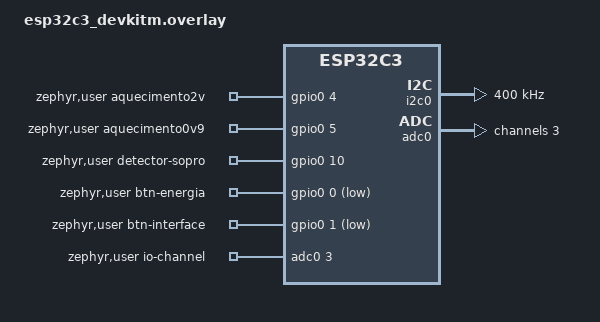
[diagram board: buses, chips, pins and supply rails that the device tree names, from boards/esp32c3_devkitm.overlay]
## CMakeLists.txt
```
cmake_minimum_required(VERSION 3.20.0)

find_package(Zephyr REQUIRED HINTS $ENV{ZEPHYR_BASE})
project(bafometro)

include(${CMAKE_CURRENT_SOURCE_DIR}/fontes.cmake)

target_include_directories(app PRIVATE ${BAFOMETRO_INCLUDES})
target_sources(app PRIVATE src/main.c ${BAFOMETRO_FONTES})
target_sources_ifdef(CONFIG_BAFOMETRO_ROTEIRO_SIMULACAO app PRIVATE src/simulacao/roteiro.c)
```

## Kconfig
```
menu "Bafômetro"

config BAFOMETRO_TEMPOS_REDUZIDOS
	bool "Tempos de espera reduzidos"
	help
	  Divide por 10 os tempos de pré-aquecimento, espera pelo sopro,
	  apresentação, recuperação e acomodação, para demonstrações em
	  hardware. A coleta de 5 s e os períodos de amostragem não mudam.

config BAFOMETRO_ROTEIRO_SIMULACAO
	bool "Roteiro de simulação"
	default y if BOARD_NATIVE_SIM
	depends on GPIO_EMUL
	help
	  Percorre o fluxo completo no native_sim, acionando o detector pelo
	  GPIO emulado e enviando comandos pela fila de eventos, e encerra a
	  simulação ao final.

endmenu

source "Kconfig.zephyr"
```

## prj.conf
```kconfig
# Máquina de estados e entradas digitais
CONFIG_SMF=y
CONFIG_GPIO=y

# Registro de eventos
CONFIG_LOG=y
CONFIG_LOG_DEFAULT_LEVEL=3

CONFIG_MAIN_STACK_SIZE=2048
```

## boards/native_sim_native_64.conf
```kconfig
# Simulação o mais rápido possível; para tempo real, execute com --rt.
CONFIG_NATIVE_SIM_SLOWDOWN_TO_REAL_TIME=n
```

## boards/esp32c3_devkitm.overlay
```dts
/*
 * ESP32-C3-DevKitM-1: pinagem de docs/hardware.md.
 * Na etapa 1 só o detector de sopro (GPIO10) é usado; para simular um sopro,
 * ligue o GPIO10 ao 3V3.
 */

#include <zephyr/dt-bindings/pinctrl/esp32c3-pinctrl.h>
#include <zephyr/dt-bindings/adc/adc.h>
#include <zephyr/dt-bindings/gpio/gpio.h>
#include <zephyr/dt-bindings/i2c/i2c.h>

&pinctrl {
	i2c0_bafometro: i2c0_bafometro {
		group1 {
			pinmux = <I2C0_SDA_GPIO6>, <I2C0_SCL_GPIO7>;
			bias-pull-up;
			drive-open-drain;
			output-high;
		};
	};
};

/* A placa habilita o SPI2 em GPIO2/6/7/10, que conflita com o I2C e o detector. */
&spi2 {
	status = "disabled";
};

&i2c0 {
	status = "okay";
	pinctrl-0 = <&i2c0_bafometro>; /* a placa usa GPIO1/GPIO3 por padrão; GPIO3 é o ADC */
	pinctrl-names = "default";
	clock-frequency = <I2C_BITRATE_FAST>; /* 400 kbit/s */
};

&adc0 {
	status = "okay";
	#address-cells = <1>;
	#size-cells = <0>;

	channel@3 {
		reg = <3>; /* ADC1_CH3 = GPIO3 */
		zephyr,gain = "ADC_GAIN_1_4"; /* atenuação 11 dB -> 0..2500 mV */
		zephyr,reference = "ADC_REF_INTERNAL"; /* única referência aceita */
		zephyr,acquisition-time = <ADC_ACQ_TIME_DEFAULT>; /* não parametrizável */
		zephyr,resolution = <12>; /* única resolução no C3 */
	};
};

/ {
	zephyr,user {
		io-channels = <&adc0 3>;
		/* Polaridade dos enables do aquecedor: confirmar no esquemático. */
		aquecimento2v-gpios = <&gpio0 4 GPIO_ACTIVE_HIGH>;
		aquecimento0v9-gpios = <&gpio0 5 GPIO_ACTIVE_HIGH>;
		detector-sopro-gpios = <&gpio0 10 (GPIO_ACTIVE_HIGH | GPIO_PULL_DOWN)>;
		btn-energia-gpios = <&gpio0 0 (GPIO_ACTIVE_LOW | GPIO_PULL_UP)>;
		btn-interface-gpios = <&gpio0 1 (GPIO_ACTIVE_LOW | GPIO_PULL_UP)>;
		/* inibidor-gpios: pino pendente (ver docs/hardware.md) */
	};
};
```

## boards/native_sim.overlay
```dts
/*
 * Detector de sopro no GPIO emulado do native_sim (pino 0).
 * O roteiro de simulação e os testes o acionam com gpio_emul_input_set().
 */

#include <zephyr/dt-bindings/gpio/gpio.h>

/ {
	zephyr,user {
		detector-sopro-gpios = <&gpio0 0 GPIO_ACTIVE_HIGH>;
	};
};
```

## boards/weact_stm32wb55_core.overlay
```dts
/*
 * Provisório (etapa 1): o botão BOOT da placa (PH3) faz o papel do detector
 * de sopro. A pinagem do bafômetro no STM32WB55 é definida na etapa 8.
 */

#include <zephyr/dt-bindings/gpio/gpio.h>

/ {
	zephyr,user {
		detector-sopro-gpios = <&gpioh 3 (GPIO_ACTIVE_HIGH | GPIO_PULL_DOWN)>;
	};
};
```

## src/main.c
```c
/*
 * Bafômetro: ponto de entrada. A única thread da aplicação processa a fila
 * de eventos e executa a máquina de estados.
 */

#include <zephyr/kernel.h>

#include "aplicacao/bafometro.h"

int main(void)
{
	(void)bafometro_iniciar();

	while (true) {
		(void)bafometro_processarProximoEvento(K_FOREVER);
	}

	return 0;
}
```

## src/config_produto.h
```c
/*
 * Parâmetros do produto: fonte única dos valores usados pela aplicação.
 * A origem de cada valor está em docs/arquitetura/arquitetura-firmware.md.
 * Só macros: este arquivo é incluído também pelo domínio, que não depende do Zephyr.
 */

#ifndef BAFOMETRO_CONFIG_PRODUTO_H
#define BAFOMETRO_CONFIG_PRODUTO_H

#if defined(CONFIG_BAFOMETRO_TEMPOS_REDUZIDOS)
#define FATOR_REDUCAO_TEMPO 10U
#else
#define FATOR_REDUCAO_TEMPO 1U
#endif

/*
 * Esperas do fluxo, divididas pelo fator de redução.
 * Pré-aquecimento: o datasheet do MQ303B (v1.4) pede 2,0 V por 5 a 10 s antes da detecção.
 */
#define TEMPO_PRE_AQUECIMENTO_MS  (10000U / FATOR_REDUCAO_TEMPO) /* datasheet: 5 a 10 s */
#define TEMPO_ESPERA_SOPRO_MS     (20000U / FATOR_REDUCAO_TEMPO) /* requisito; origem a citar */
#define TEMPO_APRESENTACAO_MS     (10000U / FATOR_REDUCAO_TEMPO) /* proposta */
#define TEMPO_MIN_ENTRE_TESTES_MS (30000U / FATOR_REDUCAO_TEMPO) /* PROVISÓRIO */
#define TEMPO_ACOMODACAO_FASE_MS  (500U / FATOR_REDUCAO_TEMPO)   /* PROVISÓRIO */

/* Medição (não são reduzidos) */
#define TEMPO_SOPRO_MINIMO_MS     5000U
#define PERIODO_AMOSTRAGEM_MS     50U   /* proposta: 20 Hz */
#define TOLERANCIA_QUEDA_SOPRO_MS 150U  /* proposta: queda acumulada tolerada durante a coleta */
#define PERIODO_CONTAGEM_MS       1000U /* contagem regressiva na tela */
#define TEMPO_TRANSIENTE_MS       2000U /* proposta: início da coleta descartado no cálculo */
#define JANELA_MEDIA_MOVEL        8U    /* proposta: faixa de 8 a 16 */
#define QTD_MAXIMA_AMOSTRAS       110U  /* 5 s a 50 ms, com margem */

/*
 * Circuito de medição do MQ303B: VCC - Rs (sensor) - nó do ADC - RL - GND.
 * O ADC mede a tensão sobre RL (VRL), como no datasheet e no texto do TCC.
 */
#define TENSAO_ALIMENTACAO_MV   3300.0f
#define RESISTENCIA_CARGA_OHMS  3300.0f
#define MARGEM_TENSAO_VALIDA_MV 1.0f /* protótipo: rejeita leituras a 1 mV dos trilhos */

/* Conversão: mg/L = ppm / 500 (protótipo; superestima de 6 a 9 % frente ao gás ideal) */
#define FATOR_PPM_PARA_MGL 500.0f

/* Qualidade: coeficiente de variação do trecho estável, em % (a revalidar) */
#define QUALIDADE_CV_EXCELENTE_PCT 2.0f
#define QUALIDADE_CV_BOA_PCT       5.0f
#define QUALIDADE_CV_ACEITAVEL_PCT 10.0f

/* Calibração do R0 */
#define QTD_AMOSTRAS_CALIBRACAO             60U
#define INTERVALO_CALIBRACAO_MS             100U
#define PORCENTAGEM_MINIMA_AMOSTRAS_VALIDAS 50U    /* protótipo */
#define R0_PADRAO_OHMS                      24000U /* valor do protótipo */

/*
 * Inibição, em milésimos de mg/L. PROVISÓRIO: definir pelo método da banda de guarda.
 * A curva começa em 50 ppm (0,100 mg/L): ar limpo é medido como 0,100 mg/L, então
 * só há liberação se LIMITE - HISTERESE for maior que 100.
 */
#define LIMITE_INIBICAO_MILESIMOS_MGL     150U
#define HISTERESE_LIBERACAO_MILESIMOS_MGL 20U

/* Fila de eventos */
#define QTD_POSICOES_FILA_EVENTOS 8

/* Derivados */
#define QTD_TIQUES_PRE_AQUECIMENTO (TEMPO_PRE_AQUECIMENTO_MS / PERIODO_CONTAGEM_MS)
#define QTD_TIQUES_COLETA          (TEMPO_SOPRO_MINIMO_MS / PERIODO_AMOSTRAGEM_MS)
#define QTD_AMOSTRAS_TRANSIENTE    (TEMPO_TRANSIENTE_MS / PERIODO_AMOSTRAGEM_MS)

#endif /* BAFOMETRO_CONFIG_PRODUTO_H */
```
